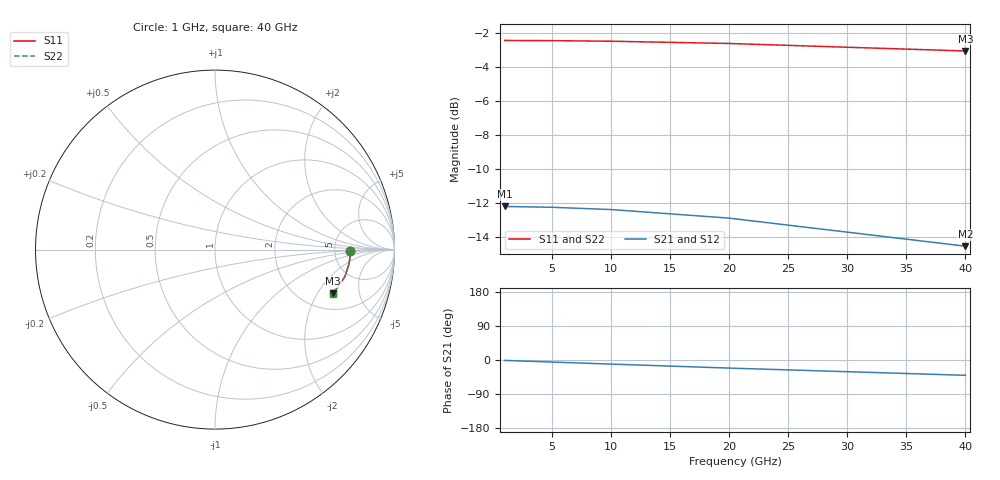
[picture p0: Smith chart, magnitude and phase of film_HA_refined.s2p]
! EM-TFR film section of run HA_refined: ha_refined_dut.s2p de-embedded by half of ha_refined_thru.s2p (README)
# GHz S RI R 50
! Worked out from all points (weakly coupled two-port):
!   5 points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, 1 GHz to 40 GHz, reference 50 ohm
!   highest |S21| = -12.21 dB at 1 GHz (marker M1); lowest = -14.5 dB at 40 GHz (marker M2)
!   lowest |S11| = -3.1 dB at 40 GHz (marker M3), VSWR 5.72, Z = 144 - j139 ohm
!   |S11| at or under -10 dB: nowhere
!   |S22| runs from -3.1 to -2.4 dB; largest |S21 - S12| = 2.5e-06
1  0.7544 -0.00844  0.2452 -0.00468  0.2452 -0.00468  0.7547 -0.00839
5  0.7524 -0.0411  0.2429 -0.0231  0.2429 -0.0231  0.7527 -0.0414
10  0.7463 -0.0806  0.2359 -0.0451  0.2359 -0.0451  0.7463 -0.0812
20  0.7236 -0.1511  0.2111 -0.0825  0.2111 -0.0825  0.723 -0.1523
40  0.6589 -0.2439  0.1428 -0.1215  0.1428 -0.1215  0.6562 -0.2462
